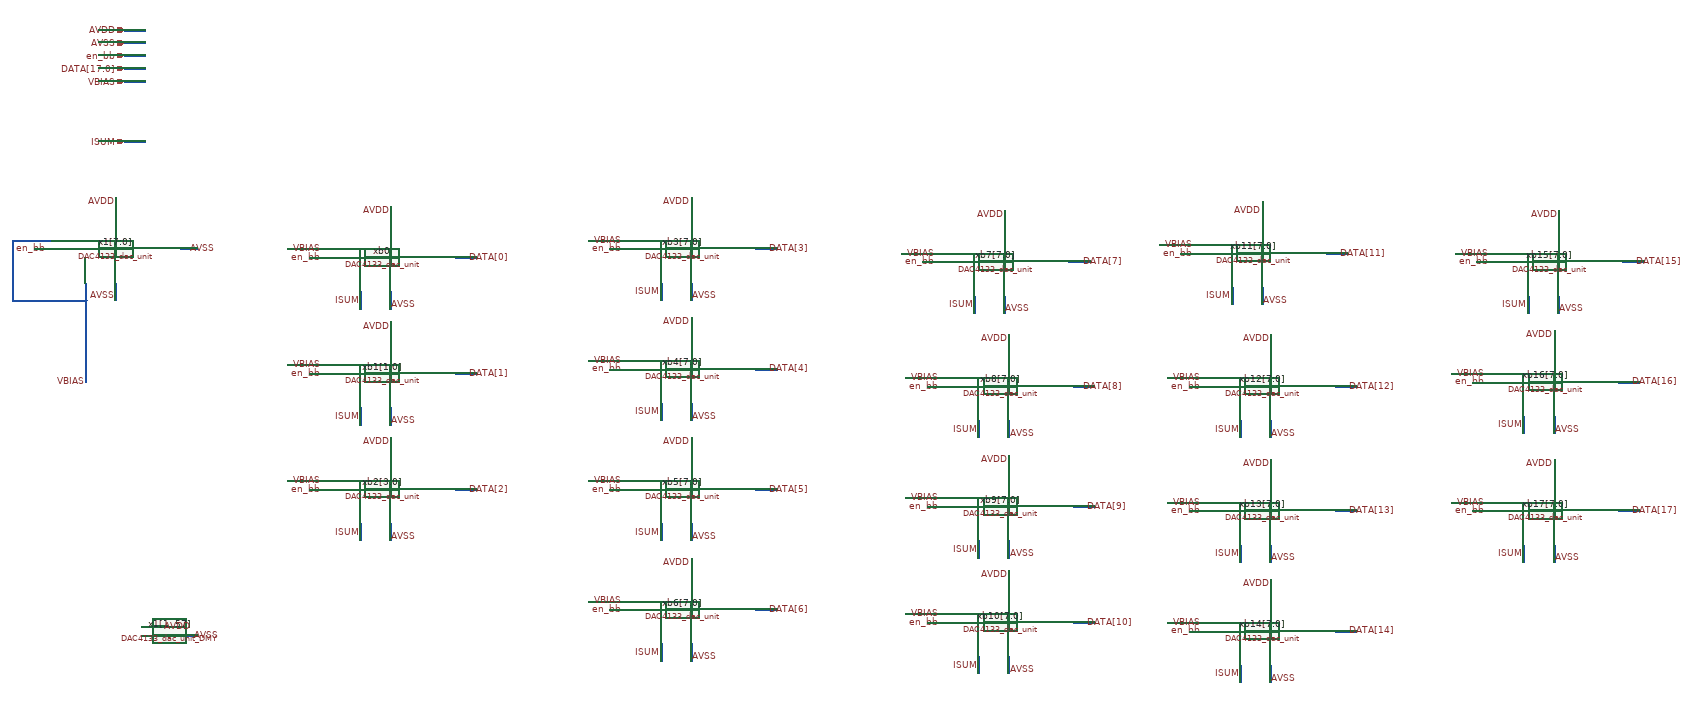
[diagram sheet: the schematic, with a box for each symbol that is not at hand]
v {xschem version=3.4.8RC file_version=1.3}
G {}
K {}
V {}
S {}
F {}
E {}
N 920 -1240 920 -1200 {lab=AVDD}
N 730 -1120 770 -1120 {lab=en_bb}
N 1070 -1120 1110 -1120 {lab=AVSS}
N 920 -1040 920 -1000 {lab=AVSS}
N 680 -1140 770 -1140 {lab=VBIAS}
N 680 -1140 680 -1000 {lab=VBIAS}
N 680 -1000 850 -1000 {lab=VBIAS}
N 850 -1040 850 -1000 {lab=VBIAS}
N 850 -1000 850 -810 {lab=VBIAS}
N 940 -1630 990 -1630 {lab=AVDD}
N 940 -1600 990 -1600 {lab=AVSS}
N 940 -1540 990 -1540 {lab=DATA[17:0]}
N 940 -1570 990 -1570 {lab=en_bb}
N 940 -1510 990 -1510 {lab=VBIAS}
N 940 -1370 990 -1370 {lab=ISUM}
N 1560 -1220 1560 -1180 {lab=AVDD}
N 1370 -1100 1410 -1100 {lab=en_bb}
N 1710 -1100 1760 -1100 {lab=DATA[0]}
N 1560 -1020 1560 -980 {lab=AVSS}
N 1320 -1120 1410 -1120 {lab=VBIAS}
N 1490 -1020 1490 -980 {lab=ISUM}
N 1560 -950 1560 -910 {lab=AVDD}
N 1370 -830 1410 -830 {lab=en_bb}
N 1710 -830 1760 -830 {lab=DATA[1]}
N 1560 -750 1560 -710 {lab=AVSS}
N 1320 -850 1410 -850 {lab=VBIAS}
N 1490 -750 1490 -710 {lab=ISUM}
N 1560 -680 1560 -640 {lab=AVDD}
N 1370 -560 1410 -560 {lab=en_bb}
N 1710 -560 1760 -560 {lab=DATA[2]}
N 1560 -480 1560 -440 {lab=AVSS}
N 1320 -580 1410 -580 {lab=VBIAS}
N 1490 -480 1490 -440 {lab=ISUM}
N 2260 -1240 2260 -1200 {lab=AVDD}
N 2070 -1120 2110 -1120 {lab=en_bb}
N 2410 -1120 2460 -1120 {lab=DATA[3]}
N 2260 -1040 2260 -1000 {lab=AVSS}
N 2020 -1140 2110 -1140 {lab=VBIAS}
N 2190 -1040 2190 -1000 {lab=ISUM}
N 2260 -960 2260 -920 {lab=AVDD}
N 2070 -840 2110 -840 {lab=en_bb}
N 2410 -840 2460 -840 {lab=DATA[4]}
N 2260 -760 2260 -720 {lab=AVSS}
N 2020 -860 2110 -860 {lab=VBIAS}
N 2190 -760 2190 -720 {lab=ISUM}
N 2260 -680 2260 -640 {lab=AVDD}
N 2070 -560 2110 -560 {lab=en_bb}
N 2410 -560 2460 -560 {lab=DATA[5]}
N 2260 -480 2260 -440 {lab=AVSS}
N 2020 -580 2110 -580 {lab=VBIAS}
N 2190 -480 2190 -440 {lab=ISUM}
N 2260 -400 2260 -360 {lab=AVDD}
N 2070 -280 2110 -280 {lab=en_bb}
N 2410 -280 2460 -280 {lab=DATA[6]}
N 2260 -200 2260 -160 {lab=AVSS}
N 2020 -300 2110 -300 {lab=VBIAS}
N 2190 -200 2190 -160 {lab=ISUM}
N 2990 -1210 2990 -1170 {lab=AVDD}
N 2800 -1090 2840 -1090 {lab=en_bb}
N 3140 -1090 3190 -1090 {lab=DATA[7]}
N 2990 -1010 2990 -970 {lab=AVSS}
N 2750 -1110 2840 -1110 {lab=VBIAS}
N 2920 -1010 2920 -970 {lab=ISUM}
N 3000 -920 3000 -880 {lab=AVDD}
N 2810 -800 2850 -800 {lab=en_bb}
N 3150 -800 3200 -800 {lab=DATA[8]}
N 3000 -720 3000 -680 {lab=AVSS}
N 2760 -820 2850 -820 {lab=VBIAS}
N 2930 -720 2930 -680 {lab=ISUM}
N 3000 -640 3000 -600 {lab=AVDD}
N 2810 -520 2850 -520 {lab=en_bb}
N 3150 -520 3200 -520 {lab=DATA[9]}
N 3000 -440 3000 -400 {lab=AVSS}
N 2760 -540 2850 -540 {lab=VBIAS}
N 2930 -440 2930 -400 {lab=ISUM}
N 3000 -370 3000 -330 {lab=AVDD}
N 2810 -250 2850 -250 {lab=en_bb}
N 3150 -250 3200 -250 {lab=DATA[10]}
N 3000 -170 3000 -130 {lab=AVSS}
N 2760 -270 2850 -270 {lab=VBIAS}
N 2930 -170 2930 -130 {lab=ISUM}
N 3590 -1230 3590 -1190 {lab=AVDD}
N 3400 -1110 3440 -1110 {lab=en_bb}
N 3740 -1110 3790 -1110 {lab=DATA[11]}
N 3590 -1030 3590 -990 {lab=AVSS}
N 3350 -1130 3440 -1130 {lab=VBIAS}
N 3520 -1030 3520 -990 {lab=ISUM}
N 3610 -920 3610 -880 {lab=AVDD}
N 3420 -800 3460 -800 {lab=en_bb}
N 3760 -800 3810 -800 {lab=DATA[12]}
N 3610 -720 3610 -680 {lab=AVSS}
N 3370 -820 3460 -820 {lab=VBIAS}
N 3540 -720 3540 -680 {lab=ISUM}
N 3610 -630 3610 -590 {lab=AVDD}
N 3420 -510 3460 -510 {lab=en_bb}
N 3760 -510 3810 -510 {lab=DATA[13]}
N 3610 -430 3610 -390 {lab=AVSS}
N 3370 -530 3460 -530 {lab=VBIAS}
N 3540 -430 3540 -390 {lab=ISUM}
N 3610 -350 3610 -310 {lab=AVDD}
N 3420 -230 3460 -230 {lab=en_bb}
N 3760 -230 3810 -230 {lab=DATA[14]}
N 3610 -150 3610 -110 {lab=AVSS}
N 3370 -250 3460 -250 {lab=VBIAS}
N 3540 -150 3540 -110 {lab=ISUM}
N 4280 -1210 4280 -1170 {lab=AVDD}
N 4090 -1090 4130 -1090 {lab=en_bb}
N 4430 -1090 4480 -1090 {lab=DATA[15]}
N 4280 -1010 4280 -970 {lab=AVSS}
N 4040 -1110 4130 -1110 {lab=VBIAS}
N 4210 -1010 4210 -970 {lab=ISUM}
N 4270 -930 4270 -890 {lab=AVDD}
N 4080 -810 4120 -810 {lab=en_bb}
N 4420 -810 4470 -810 {lab=DATA[16]}
N 4270 -730 4270 -690 {lab=AVSS}
N 4200 -730 4200 -690 {lab=ISUM}
N 4270 -630 4270 -590 {lab=AVDD}
N 4080 -510 4120 -510 {lab=en_bb}
N 4420 -510 4470 -510 {lab=DATA[17]}
N 4270 -430 4270 -390 {lab=AVSS}
N 4200 -430 4200 -390 {lab=ISUM}
N 4030 -830 4120 -830 {lab=VBIAS}
N 4030 -530 4120 -530 {lab=VBIAS}
N 980 -240 1040 -240 {lab=AVDD}
N 980 -220 1110 -220 {lab=AVSS}
C {lab_wire.sym} 850 -810 0 0 {name=p13 sig_type=std_logic lab=VBIAS}
C {lab_wire.sym} 920 -1010 0 0 {name=p18 sig_type=std_logic lab=AVSS}
C {lab_wire.sym} 920 -1230 0 0 {name=p19 sig_type=std_logic lab=AVDD}
C {lab_wire.sym} 760 -1120 0 0 {name=p21 sig_type=std_logic lab=en_bb}
C {lab_wire.sym} 1090 -1120 0 1 {name=p28 sig_type=std_logic lab=AVSS}
C {iopin.sym} 940 -1630 2 0 {name=p721 lab=AVDD}
C {iopin.sym} 940 -1600 2 0 {name=p722 lab=AVSS}
C {iopin.sym} 940 -1570 2 0 {name=p724 lab=en_bb}
C {iopin.sym} 940 -1540 2 0 {name=p727 lab=DATA[17:0]}
C {iopin.sym} 940 -1510 2 0 {name=p1 lab=VBIAS}
C {iopin.sym} 940 -1370 2 0 {name=p6 lab=ISUM}
C {lab_wire.sym} 1560 -1210 0 0 {name=p9 sig_type=std_logic lab=AVDD}
C {lab_wire.sym} 1400 -1100 0 0 {name=p11 sig_type=std_logic lab=en_bb}
C {DAC4133_dac_unit.sym} 1560 -1100 0 0 {name=xb0}
C {lab_wire.sym} 1400 -1120 0 0 {name=p36 sig_type=std_logic lab=VBIAS}
C {lab_wire.sym} 1560 -990 0 1 {name=p37 sig_type=std_logic lab=AVSS}
C {lab_wire.sym} 1490 -1000 0 0 {name=p38 sig_type=std_logic lab=ISUM}
C {lab_wire.sym} 1560 -940 0 0 {name=p27 sig_type=std_logic lab=AVDD}
C {lab_wire.sym} 1400 -830 0 0 {name=p40 sig_type=std_logic lab=en_bb}
C {DAC4133_dac_unit.sym} 1560 -830 0 0 {name=xb1[1:0]}
C {lab_wire.sym} 1400 -850 0 0 {name=p41 sig_type=std_logic lab=VBIAS}
C {lab_wire.sym} 1560 -720 0 1 {name=p42 sig_type=std_logic lab=AVSS}
C {lab_wire.sym} 1490 -730 0 0 {name=p43 sig_type=std_logic lab=ISUM}
C {lab_wire.sym} 1560 -670 0 0 {name=p47 sig_type=std_logic lab=AVDD}
C {lab_wire.sym} 1400 -560 0 0 {name=p48 sig_type=std_logic lab=en_bb}
C {DAC4133_dac_unit.sym} 1560 -560 0 0 {name=xb2[3:0]}
C {lab_wire.sym} 1400 -580 0 0 {name=p49 sig_type=std_logic lab=VBIAS}
C {lab_wire.sym} 1560 -450 0 1 {name=p55 sig_type=std_logic lab=AVSS}
C {lab_wire.sym} 1490 -460 0 0 {name=p56 sig_type=std_logic lab=ISUM}
C {lab_wire.sym} 2260 -1230 0 0 {name=p61 sig_type=std_logic lab=AVDD}
C {lab_wire.sym} 2100 -1120 0 0 {name=p62 sig_type=std_logic lab=en_bb}
C {DAC4133_dac_unit.sym} 2260 -1120 0 0 {name=xb3[7:0]}
C {lab_wire.sym} 2100 -1140 0 0 {name=p63 sig_type=std_logic lab=VBIAS}
C {lab_wire.sym} 2260 -1010 0 1 {name=p64 sig_type=std_logic lab=AVSS}
C {lab_wire.sym} 2190 -1020 0 0 {name=p65 sig_type=std_logic lab=ISUM}
C {lab_wire.sym} 2260 -950 0 0 {name=p70 sig_type=std_logic lab=AVDD}
C {lab_wire.sym} 2100 -840 0 0 {name=p71 sig_type=std_logic lab=en_bb}
C {DAC4133_dac_unit.sym} 2260 -840 0 0 {name=xb4[7:0]}
C {lab_wire.sym} 2100 -860 0 0 {name=p72 sig_type=std_logic lab=VBIAS}
C {lab_wire.sym} 2260 -730 0 1 {name=p73 sig_type=std_logic lab=AVSS}
C {lab_wire.sym} 2190 -740 0 0 {name=p74 sig_type=std_logic lab=ISUM}
C {lab_wire.sym} 2260 -670 0 0 {name=p76 sig_type=std_logic lab=AVDD}
C {lab_wire.sym} 2100 -560 0 0 {name=p77 sig_type=std_logic lab=en_bb}
C {DAC4133_dac_unit.sym} 2260 -560 0 0 {name=xb5[7:0]}
C {lab_wire.sym} 2100 -580 0 0 {name=p78 sig_type=std_logic lab=VBIAS}
C {lab_wire.sym} 2260 -450 0 1 {name=p79 sig_type=std_logic lab=AVSS}
C {lab_wire.sym} 2190 -460 0 0 {name=p80 sig_type=std_logic lab=ISUM}
C {lab_wire.sym} 2260 -390 0 0 {name=p82 sig_type=std_logic lab=AVDD}
C {lab_wire.sym} 2100 -280 0 0 {name=p83 sig_type=std_logic lab=en_bb}
C {DAC4133_dac_unit.sym} 2260 -280 0 0 {name=xb6[7:0]}
C {lab_wire.sym} 2100 -300 0 0 {name=p84 sig_type=std_logic lab=VBIAS}
C {lab_wire.sym} 2260 -170 0 1 {name=p85 sig_type=std_logic lab=AVSS}
C {lab_wire.sym} 2190 -180 0 0 {name=p86 sig_type=std_logic lab=ISUM}
C {lab_wire.sym} 2990 -1200 0 0 {name=p88 sig_type=std_logic lab=AVDD}
C {lab_wire.sym} 2830 -1090 0 0 {name=p89 sig_type=std_logic lab=en_bb}
C {DAC4133_dac_unit.sym} 2990 -1090 0 0 {name=xb7[7:0]}
C {lab_wire.sym} 2830 -1110 0 0 {name=p90 sig_type=std_logic lab=VBIAS}
C {lab_wire.sym} 2990 -980 0 1 {name=p91 sig_type=std_logic lab=AVSS}
C {lab_wire.sym} 2920 -990 0 0 {name=p92 sig_type=std_logic lab=ISUM}
C {lab_wire.sym} 3000 -910 0 0 {name=p94 sig_type=std_logic lab=AVDD}
C {lab_wire.sym} 2840 -800 0 0 {name=p95 sig_type=std_logic lab=en_bb}
C {DAC4133_dac_unit.sym} 3000 -800 0 0 {name=xb8[7:0]}
C {lab_wire.sym} 2840 -820 0 0 {name=p96 sig_type=std_logic lab=VBIAS}
C {lab_wire.sym} 3000 -690 0 1 {name=p97 sig_type=std_logic lab=AVSS}
C {lab_wire.sym} 2930 -700 0 0 {name=p98 sig_type=std_logic lab=ISUM}
C {lab_wire.sym} 3000 -630 0 0 {name=p100 sig_type=std_logic lab=AVDD}
C {lab_wire.sym} 2840 -520 0 0 {name=p101 sig_type=std_logic lab=en_bb}
C {DAC4133_dac_unit.sym} 3000 -520 0 0 {name=xb9[7:0]}
C {lab_wire.sym} 2840 -540 0 0 {name=p102 sig_type=std_logic lab=VBIAS}
C {lab_wire.sym} 3000 -410 0 1 {name=p103 sig_type=std_logic lab=AVSS}
C {lab_wire.sym} 2930 -420 0 0 {name=p104 sig_type=std_logic lab=ISUM}
C {lab_wire.sym} 3000 -360 0 0 {name=p106 sig_type=std_logic lab=AVDD}
C {lab_wire.sym} 2840 -250 0 0 {name=p111 sig_type=std_logic lab=en_bb}
C {DAC4133_dac_unit.sym} 3000 -250 0 0 {name=xb10[7:0]}
C {lab_wire.sym} 2840 -270 0 0 {name=p112 sig_type=std_logic lab=VBIAS}
C {lab_wire.sym} 3000 -140 0 1 {name=p114 sig_type=std_logic lab=AVSS}
C {lab_wire.sym} 2930 -150 0 0 {name=p115 sig_type=std_logic lab=ISUM}
C {lab_wire.sym} 3590 -1210 0 0 {name=p117 sig_type=std_logic lab=AVDD}
C {lab_wire.sym} 3430 -1110 0 0 {name=p118 sig_type=std_logic lab=en_bb}
C {DAC4133_dac_unit.sym} 3590 -1110 0 0 {name=xb11[7:0]}
C {lab_wire.sym} 3430 -1130 0 0 {name=p119 sig_type=std_logic lab=VBIAS}
C {lab_wire.sym} 3590 -1000 0 1 {name=p120 sig_type=std_logic lab=AVSS}
C {lab_wire.sym} 3520 -1010 0 0 {name=p121 sig_type=std_logic lab=ISUM}
C {lab_wire.sym} 3610 -910 0 0 {name=p123 sig_type=std_logic lab=AVDD}
C {lab_wire.sym} 3450 -800 0 0 {name=p124 sig_type=std_logic lab=en_bb}
C {DAC4133_dac_unit.sym} 3610 -800 0 0 {name=xb12[7:0]}
C {lab_wire.sym} 3450 -820 0 0 {name=p125 sig_type=std_logic lab=VBIAS}
C {lab_wire.sym} 3610 -690 0 1 {name=p126 sig_type=std_logic lab=AVSS}
C {lab_wire.sym} 3540 -700 0 0 {name=p127 sig_type=std_logic lab=ISUM}
C {lab_wire.sym} 3610 -620 0 0 {name=p129 sig_type=std_logic lab=AVDD}
C {lab_wire.sym} 3450 -510 0 0 {name=p130 sig_type=std_logic lab=en_bb}
C {DAC4133_dac_unit.sym} 3610 -510 0 0 {name=xb13[7:0]}
C {lab_wire.sym} 3450 -530 0 0 {name=p131 sig_type=std_logic lab=VBIAS}
C {lab_wire.sym} 3610 -400 0 1 {name=p132 sig_type=std_logic lab=AVSS}
C {lab_wire.sym} 3540 -410 0 0 {name=p133 sig_type=std_logic lab=ISUM}
C {lab_wire.sym} 3610 -340 0 0 {name=p135 sig_type=std_logic lab=AVDD}
C {lab_wire.sym} 3450 -230 0 0 {name=p136 sig_type=std_logic lab=en_bb}
C {DAC4133_dac_unit.sym} 3610 -230 0 0 {name=xb14[7:0]}
C {lab_wire.sym} 3450 -250 0 0 {name=p137 sig_type=std_logic lab=VBIAS}
C {lab_wire.sym} 3610 -120 0 1 {name=p138 sig_type=std_logic lab=AVSS}
C {lab_wire.sym} 3540 -130 0 0 {name=p139 sig_type=std_logic lab=ISUM}
C {lab_wire.sym} 4280 -1200 0 0 {name=p141 sig_type=std_logic lab=AVDD}
C {lab_wire.sym} 4120 -1090 0 0 {name=p142 sig_type=std_logic lab=en_bb}
C {DAC4133_dac_unit.sym} 4280 -1090 0 0 {name=xb15[7:0]}
C {lab_wire.sym} 4120 -1110 0 0 {name=p143 sig_type=std_logic lab=VBIAS}
C {lab_wire.sym} 4280 -980 0 1 {name=p144 sig_type=std_logic lab=AVSS}
C {lab_wire.sym} 4210 -990 0 0 {name=p145 sig_type=std_logic lab=ISUM}
C {lab_wire.sym} 4270 -920 0 0 {name=p147 sig_type=std_logic lab=AVDD}
C {lab_wire.sym} 4110 -810 0 0 {name=p148 sig_type=std_logic lab=en_bb}
C {DAC4133_dac_unit.sym} 4270 -810 0 0 {name=xb16[7:0]}
C {lab_wire.sym} 4110 -830 0 0 {name=p149 sig_type=std_logic lab=VBIAS}
C {lab_wire.sym} 4270 -700 0 1 {name=p150 sig_type=std_logic lab=AVSS}
C {lab_wire.sym} 4200 -710 0 0 {name=p151 sig_type=std_logic lab=ISUM}
C {lab_wire.sym} 4270 -620 0 0 {name=p153 sig_type=std_logic lab=AVDD}
C {lab_wire.sym} 4110 -510 0 0 {name=p154 sig_type=std_logic lab=en_bb}
C {DAC4133_dac_unit.sym} 4270 -510 0 0 {name=xb17[7:0]}
C {lab_wire.sym} 4110 -530 0 0 {name=p155 sig_type=std_logic lab=VBIAS}
C {lab_wire.sym} 4270 -400 0 1 {name=p156 sig_type=std_logic lab=AVSS}
C {lab_wire.sym} 4200 -410 0 0 {name=p157 sig_type=std_logic lab=ISUM}
C {lab_wire.sym} 1740 -1100 0 1 {name=p22 sig_type=std_logic lab=DATA[0]}
C {lab_wire.sym} 1740 -830 0 1 {name=p23 sig_type=std_logic lab=DATA[1]}
C {lab_wire.sym} 1740 -560 0 1 {name=p26 sig_type=std_logic lab=DATA[2]}
C {lab_wire.sym} 2440 -1120 0 1 {name=p29 sig_type=std_logic lab=DATA[3]}
C {lab_wire.sym} 2440 -840 0 1 {name=p39 sig_type=std_logic lab=DATA[4]}
C {lab_wire.sym} 2440 -560 0 1 {name=p46 sig_type=std_logic lab=DATA[5]}
C {lab_wire.sym} 2440 -280 0 1 {name=p51 sig_type=std_logic lab=DATA[6]}
C {lab_wire.sym} 3170 -1090 0 1 {name=p52 sig_type=std_logic lab=DATA[7]}
C {lab_wire.sym} 3170 -800 0 1 {name=p53 sig_type=std_logic lab=DATA[8]}
C {lab_wire.sym} 3180 -520 0 1 {name=p54 sig_type=std_logic lab=DATA[9]}
C {lab_wire.sym} 3180 -250 0 1 {name=p57 sig_type=std_logic lab=DATA[10]}
C {lab_wire.sym} 3770 -1110 0 1 {name=p58 sig_type=std_logic lab=DATA[11]}
C {lab_wire.sym} 3790 -800 0 1 {name=p59 sig_type=std_logic lab=DATA[12]}
C {lab_wire.sym} 3790 -510 0 1 {name=p60 sig_type=std_logic lab=DATA[13]}
C {lab_wire.sym} 3790 -230 0 1 {name=p66 sig_type=std_logic lab=DATA[14]}
C {lab_wire.sym} 4460 -1090 0 1 {name=p67 sig_type=std_logic lab=DATA[15]}
C {lab_wire.sym} 4450 -810 0 1 {name=p69 sig_type=std_logic lab=DATA[16]}
C {lab_wire.sym} 4450 -510 0 1 {name=p75 sig_type=std_logic lab=DATA[17]}
C {DAC4133_dac_unit.sym} 920 -1120 0 0 {name=x1[7:0]}
C {DAC4133_dac_unit_DMY.sym} 830 -230 0 0 {name=x1[1..57]}
C {lab_wire.sym} 1100 -220 0 1 {name=p50 sig_type=std_logic lab=AVSS}
C {lab_wire.sym} 1030 -240 0 1 {name=p68 sig_type=std_logic lab=AVDD
}
